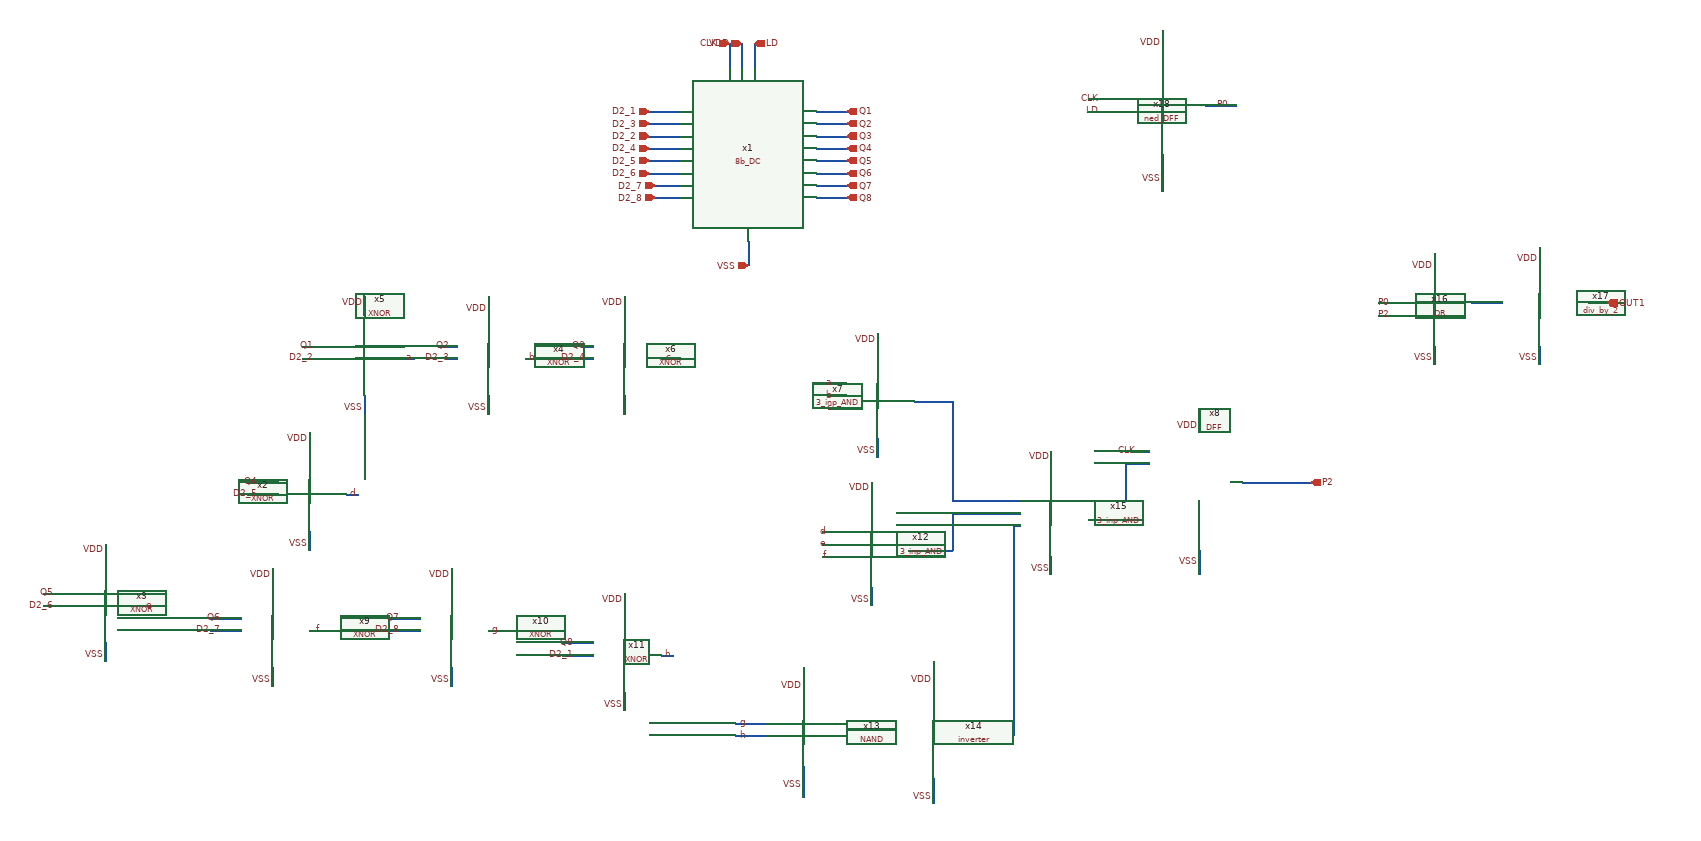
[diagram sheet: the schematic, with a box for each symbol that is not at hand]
v {xschem version=3.1.0 file_version=1.2
}
G {}
K {}
V {}
S {}
E {}
N -320 -300 -320 -260 {
lab=VDD}
N -310 20 -310 60 {
lab=VSS}
N -340 -300 -340 -260 {
lab=CLK}
N -300 -300 -300 -260 {
lab=LD}
N -470 -190 -420 -190 {
lab=D2_1}
N -470 -170 -420 -170 {
lab=D2_3}
N -470 -150 -420 -150 {
lab=D2_2}
N -470 -130 -420 -130 {
lab=D2_4}
N -470 -110 -420 -110 {
lab=D2_5}
N -470 -90 -420 -90 {
lab=D2_6}
N -460 -70 -420 -70 {
lab=D2_7}
N -460 -50 -420 -50 {
lab=D2_8}
N -200 -190 -150 -190 {
lab=Q1}
N -200 -170 -150 -170 {
lab=Q2}
N -200 -150 -150 -150 {
lab=Q3}
N -200 -130 -150 -130 {
lab=Q4}
N -200 -110 -150 -110 {
lab=Q5}
N -200 -90 -150 -90 {
lab=Q6}
N -200 -70 -150 -70 {
lab=Q7}
N -200 -50 -150 -50 {
lab=Q8}
N -1030 190 -980 190 {
lab=Q1}
N -1030 210 -980 210 {
lab=D2_2}
N -810 190 -780 190 {
lab=Q2}
N -800 210 -780 210 {
lab=D2_3}
N -580 190 -560 190 {
lab=Q3}
N -580 210 -560 210 {
lab=D2_4}
N -670 210 -640 210 {
lab=b}
N -930 110 -930 140 {
lab=VDD}
N -930 270 -930 300 {
lab=VSS}
N -730 110 -730 140 {
lab=VDD}
N -730 270 -730 300 {
lab=VSS}
N -510 110 -510 140 {
lab=VDD}
N -510 270 -510 300 {
lab=#net1}
N -450 210 -420 210 {
lab=c}
N -870 210 -850 210 {
lab=a}
N -180 250 -150 250 {
lab=a}
N -180 270 -150 270 {
lab=b}
N -180 290 -150 290 {
lab=c}
N -100 170 -100 200 {
lab=VDD}
N 490 410 530 410 {
lab=P2}
N 530 410 600 410 {
lab=P2}
N 420 290 420 330 {
lab=VDD}
N 420 520 420 560 {
lab=VSS}
N 310 360 340 360 {
lab=CLK}
N -1120 410 -1070 410 {
lab=Q4}
N -1120 430 -1070 430 {
lab=D2_5}
N -1020 330 -1020 360 {
lab=VDD}
N -1020 490 -1020 520 {
lab=VSS}
N -960 430 -940 430 {
lab=d}
N -1450 590 -1400 590 {
lab=Q5}
N -1450 610 -1400 610 {
lab=D2_6}
N -1350 510 -1350 540 {
lab=VDD}
N -1350 670 -1350 700 {
lab=VSS}
N -1290 610 -1270 610 {
lab=e}
N -1180 630 -1130 630 {
lab=Q6}
N -1180 650 -1130 650 {
lab=D2_7}
N -1080 550 -1080 580 {
lab=VDD}
N -1080 710 -1080 740 {
lab=VSS}
N -1020 650 -1000 650 {
lab=f}
N -890 630 -840 630 {
lab=Q7}
N -890 650 -840 650 {
lab=D2_8}
N -790 550 -790 580 {
lab=VDD}
N -790 710 -790 740 {
lab=VSS}
N -730 650 -710 650 {
lab=g}
N -610 670 -560 670 {
lab=Q8}
N -610 690 -560 690 {
lab=D2_1}
N -510 590 -510 620 {
lab=VDD}
N -510 750 -510 780 {
lab=VSS}
N -450 690 -430 690 {
lab=h}
N -100 340 -100 370 {
lab=VSS}
N -190 490 -160 490 {
lab=d}
N -190 510 -160 510 {
lab=e}
N -190 530 -160 530 {
lab=f}
N -110 410 -110 440 {
lab=VDD}
N -110 580 -110 610 {
lab=VSS}
N -150 810 -70 810 {
lab=#net2}
N -220 710 -220 750 {
lab=VDD}
N -220 870 -220 920 {
lab=VSS}
N -10 700 -10 750 {
lab=VDD}
N -10 890 -10 930 {
lab=VSS}
N -330 800 -280 800 {
lab=g}
N -330 820 -280 820 {
lab=h}
N 100 440 130 440 {
lab=#net3}
N 100 460 130 460 {
lab=#net4}
N 180 360 180 390 {
lab=VDD}
N 180 530 180 560 {
lab=VSS}
N -40 280 20 280 {
lab=#net3}
N 20 280 20 440 {
lab=#net3}
N 20 440 100 440 {
lab=#net3}
N -50 520 20 520 {
lab=#net4}
N 20 460 20 520 {
lab=#net4}
N 20 460 100 460 {
lab=#net4}
N 120 480 130 480 {
lab=#net5}
N 300 380 340 380 {
lab=#net6}
N 300 380 300 470 {
lab=#net6}
N 240 470 300 470 {
lab=#net6}
N 710 120 750 120 {
lab=P0}
N 710 140 750 140 {
lab=P2}
N 800 40 800 70 {
lab=VDD}
N 800 190 800 220 {
lab=VSS}
N 860 120 910 120 {
lab=#net7}
N 970 30 970 60 {
lab=VDD}
N 970 190 970 220 {
lab=VSS}
N 1050 120 1090 120 {
lab=OUT1}
N 240 -210 290 -210 {
lab=CLK}
N 240 -190 290 -190 {
lab=LD}
N 360 -320 360 -270 {
lab=VDD}
N 360 -120 360 -60 {
lab=VSS}
N 430 -200 480 -200 {
lab=P0}
N 120 480 120 820 {
lab=#net5}
C {8b_DC.sym} -270 -110 0 0 {name=x1}
C {devices/iopin.sym} -320 -300 3 0 {name=p1 lab=VDD}
C {devices/iopin.sym} -310 60 1 0 {name=p2 lab=VSS}
C {devices/ipin.sym} -470 -190 0 0 {name=p3 lab=D2_1}
C {devices/ipin.sym} -340 -300 1 0 {name=p4 lab=CLK}
C {devices/ipin.sym} -470 -150 0 0 {name=p5 lab=D2_2}
C {devices/ipin.sym} -470 -170 0 0 {name=p6 lab=D2_3}
C {devices/ipin.sym} -470 -130 0 0 {name=p7 lab=D2_4}
C {devices/ipin.sym} -470 -110 0 0 {name=p8 lab=D2_5}
C {devices/ipin.sym} -470 -90 0 0 {name=p9 lab=D2_6}
C {devices/ipin.sym} -460 -70 0 0 {name=p10 lab=D2_7}
C {devices/ipin.sym} -460 -50 0 0 {name=p11 lab=D2_8}
C {devices/opin.sym} -300 -300 3 0 {name=p12 lab=LD}
C {devices/opin.sym} -150 -190 0 0 {name=p13 lab=Q1}
C {devices/opin.sym} -150 -170 0 0 {name=p14 lab=Q2}
C {devices/opin.sym} -150 -150 0 0 {name=p15 lab=Q3}
C {devices/opin.sym} -150 -130 0 0 {name=p16 lab=Q4}
C {devices/opin.sym} -150 -110 0 0 {name=p17 lab=Q5}
C {devices/opin.sym} -150 -90 0 0 {name=p18 lab=Q6}
C {devices/opin.sym} -150 -70 0 0 {name=p19 lab=Q7}
C {devices/opin.sym} -150 -50 0 0 {name=p20 lab=Q8}
C {XNOR.sym} -630 210 0 0 {name=x4}
C {XNOR.sym} -830 210 0 0 {name=x5}
C {XNOR.sym} -410 210 0 0 {name=x6}
C {devices/lab_wire.sym} -930 120 0 0 {name=p21 sig_type=std_logic lab=VDD}
C {devices/lab_wire.sym} -730 130 0 0 {name=p22 sig_type=std_logic lab=VDD}
C {devices/lab_wire.sym} -510 120 0 0 {name=p23 sig_type=std_logic lab=VDD}
C {devices/lab_wire.sym} -930 290 0 0 {name=p24 sig_type=std_logic lab=VSS}
C {devices/lab_wire.sym} -730 290 0 0 {name=p25 sig_type=std_logic lab=VSS}
C {devices/lab_wire.sym} -100 360 0 0 {name=p26 sig_type=std_logic lab=VSS}
C {devices/lab_wire.sym} -1010 190 0 0 {name=p27 sig_type=std_logic lab=Q1}
C {devices/lab_wire.sym} -790 190 0 0 {name=p28 sig_type=std_logic lab=Q2}
C {devices/lab_wire.sym} -570 190 0 0 {name=p29 sig_type=std_logic lab=Q3}
C {devices/lab_wire.sym} -570 210 0 0 {name=p30 sig_type=std_logic lab=D2_4}
C {devices/lab_wire.sym} -790 210 0 0 {name=p31 sig_type=std_logic lab=D2_3}
C {devices/lab_wire.sym} -1010 210 0 0 {name=p32 sig_type=std_logic lab=D2_2}
C {3_inp_AND.sym} 0 270 0 0 {name=x7}
C {devices/lab_wire.sym} -100 180 0 0 {name=p33 sig_type=std_logic lab=VDD}
C {devices/lab_wire.sym} -850 210 0 0 {name=p35 sig_type=std_logic lab=a}
C {devices/lab_wire.sym} -650 210 0 0 {name=p36 sig_type=std_logic lab=b}
C {devices/lab_wire.sym} -430 210 0 0 {name=p37 sig_type=std_logic lab=c}
C {devices/lab_wire.sym} -170 250 0 0 {name=p38 sig_type=std_logic lab=a}
C {devices/opin.sym} 600 410 0 0 {name=p43 lab=P2}
C {devices/lab_wire.sym} 420 320 0 0 {name=p41 sig_type=std_logic lab=VDD}
C {devices/lab_wire.sym} 420 540 0 0 {name=p42 sig_type=std_logic lab=VSS}
C {devices/lab_wire.sym} 320 360 0 0 {name=p44 sig_type=std_logic lab=CLK}
C {DFF.sym} 490 380 0 0 {name=x8}
C {XNOR.sym} -920 430 0 0 {name=x2}
C {devices/lab_wire.sym} -1020 340 0 0 {name=p45 sig_type=std_logic lab=VDD}
C {devices/lab_wire.sym} -1020 510 0 0 {name=p46 sig_type=std_logic lab=VSS}
C {devices/lab_wire.sym} -1100 410 0 0 {name=p47 sig_type=std_logic lab=Q4}
C {devices/lab_wire.sym} -1100 430 0 0 {name=p48 sig_type=std_logic lab=D2_5}
C {devices/lab_wire.sym} -940 430 0 0 {name=p49 sig_type=std_logic lab=d}
C {XNOR.sym} -1250 610 0 0 {name=x3}
C {devices/lab_wire.sym} -1350 520 0 0 {name=p50 sig_type=std_logic lab=VDD}
C {devices/lab_wire.sym} -1350 690 0 0 {name=p51 sig_type=std_logic lab=VSS}
C {devices/lab_wire.sym} -1430 590 0 0 {name=p52 sig_type=std_logic lab=Q5}
C {devices/lab_wire.sym} -1430 610 0 0 {name=p53 sig_type=std_logic lab=D2_6}
C {devices/lab_wire.sym} -1270 610 0 0 {name=p54 sig_type=std_logic lab=e}
C {XNOR.sym} -980 650 0 0 {name=x9}
C {devices/lab_wire.sym} -1080 560 0 0 {name=p55 sig_type=std_logic lab=VDD}
C {devices/lab_wire.sym} -1080 730 0 0 {name=p56 sig_type=std_logic lab=VSS}
C {devices/lab_wire.sym} -1160 630 0 0 {name=p57 sig_type=std_logic lab=Q6}
C {devices/lab_wire.sym} -1160 650 0 0 {name=p58 sig_type=std_logic lab=D2_7}
C {devices/lab_wire.sym} -1000 650 0 0 {name=p59 sig_type=std_logic lab=f}
C {XNOR.sym} -690 650 0 0 {name=x10}
C {devices/lab_wire.sym} -790 560 0 0 {name=p60 sig_type=std_logic lab=VDD}
C {devices/lab_wire.sym} -790 730 0 0 {name=p61 sig_type=std_logic lab=VSS}
C {devices/lab_wire.sym} -870 630 0 0 {name=p62 sig_type=std_logic lab=Q7}
C {devices/lab_wire.sym} -870 650 0 0 {name=p63 sig_type=std_logic lab=D2_8}
C {devices/lab_wire.sym} -710 650 0 0 {name=p64 sig_type=std_logic lab=g}
C {XNOR.sym} -410 690 0 0 {name=x11}
C {devices/lab_wire.sym} -510 600 0 0 {name=p65 sig_type=std_logic lab=VDD}
C {devices/lab_wire.sym} -510 770 0 0 {name=p66 sig_type=std_logic lab=VSS}
C {devices/lab_wire.sym} -590 670 0 0 {name=p67 sig_type=std_logic lab=Q8}
C {devices/lab_wire.sym} -590 690 0 0 {name=p68 sig_type=std_logic lab=D2_1}
C {devices/lab_wire.sym} -430 690 0 0 {name=p69 sig_type=std_logic lab=h}
C {devices/lab_wire.sym} -110 600 0 0 {name=p34 sig_type=std_logic lab=VSS}
C {3_inp_AND.sym} -10 510 0 0 {name=x12}
C {devices/lab_wire.sym} -110 420 0 0 {name=p70 sig_type=std_logic lab=VDD}
C {devices/lab_wire.sym} -180 490 0 0 {name=p71 sig_type=std_logic lab=d}
C {devices/lab_wire.sym} -180 510 0 0 {name=p72 sig_type=std_logic lab=e}
C {devices/lab_wire.sym} -180 530 0 0 {name=p73 sig_type=std_logic lab=f}
C {NAND.sym} -130 820 0 0 {name=x13}
C {inverter.sym} 80 830 0 0 {name=x14}
C {devices/lab_wire.sym} -310 820 0 0 {name=p75 sig_type=std_logic lab=h}
C {devices/lab_wire.sym} -220 740 0 0 {name=p76 sig_type=std_logic lab=VDD}
C {devices/lab_wire.sym} -220 900 0 0 {name=p77 sig_type=std_logic lab=VSS}
C {devices/lab_wire.sym} -10 730 0 0 {name=p78 sig_type=std_logic lab=VDD}
C {devices/lab_wire.sym} -10 920 0 0 {name=p79 sig_type=std_logic lab=VSS}
C {devices/lab_wire.sym} 180 550 0 0 {name=p80 sig_type=std_logic lab=VSS}
C {3_inp_AND.sym} 280 460 0 0 {name=x15}
C {devices/lab_wire.sym} 180 370 0 0 {name=p81 sig_type=std_logic lab=VDD}
C {OR.sym} 900 140 0 0 {name=x16}
C {devices/lab_wire.sym} 730 120 0 0 {name=p82 sig_type=std_logic lab=P0}
C {devices/lab_wire.sym} 730 140 0 0 {name=p83 sig_type=std_logic lab=P2}
C {devices/lab_wire.sym} 800 60 0 0 {name=p84 sig_type=std_logic lab=VDD}
C {devices/lab_wire.sym} 800 210 0 0 {name=p85 sig_type=std_logic lab=VSS}
C {div_by_2.sym} 1060 140 0 0 {name=x17}
C {devices/lab_wire.sym} 970 50 0 0 {name=p86 sig_type=std_logic lab=VDD}
C {devices/lab_wire.sym} 970 210 0 0 {name=p87 sig_type=std_logic lab=VSS}
C {devices/opin.sym} 1080 120 0 0 {name=p88 lab=OUT1}
C {devices/lab_wire.sym} 260 -210 0 0 {name=p89 sig_type=std_logic lab=CLK}
C {devices/lab_wire.sym} 360 -300 0 0 {name=p91 sig_type=std_logic lab=VDD}
C {devices/lab_wire.sym} 360 -80 0 0 {name=p92 sig_type=std_logic lab=VSS}
C {devices/lab_wire.sym} 470 -200 0 0 {name=p93 sig_type=std_logic lab=P0}
C {devices/lab_wire.sym} 260 -190 0 0 {name=p90 sig_type=std_logic lab=LD}
C {devices/lab_wire.sym} -170 270 0 0 {name=p94 sig_type=std_logic lab=b}
C {devices/lab_wire.sym} -170 290 0 0 {name=p95 sig_type=std_logic lab=c}
C {devices/lab_wire.sym} -310 800 0 0 {name=p39 sig_type=std_logic lab=g}
C {ned_DFF.sym} 440 -190 0 0 {name=x18}
